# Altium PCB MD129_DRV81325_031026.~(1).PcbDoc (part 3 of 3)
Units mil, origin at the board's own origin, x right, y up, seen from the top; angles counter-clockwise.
Board outline 4300.91 x 4001.52 mil, 4 copper layers (Top Layer, GND, PWR, Bottom Layer), stack 92.668 mil thick; 212 components, 89 nets, 489 pads, 980 vias.

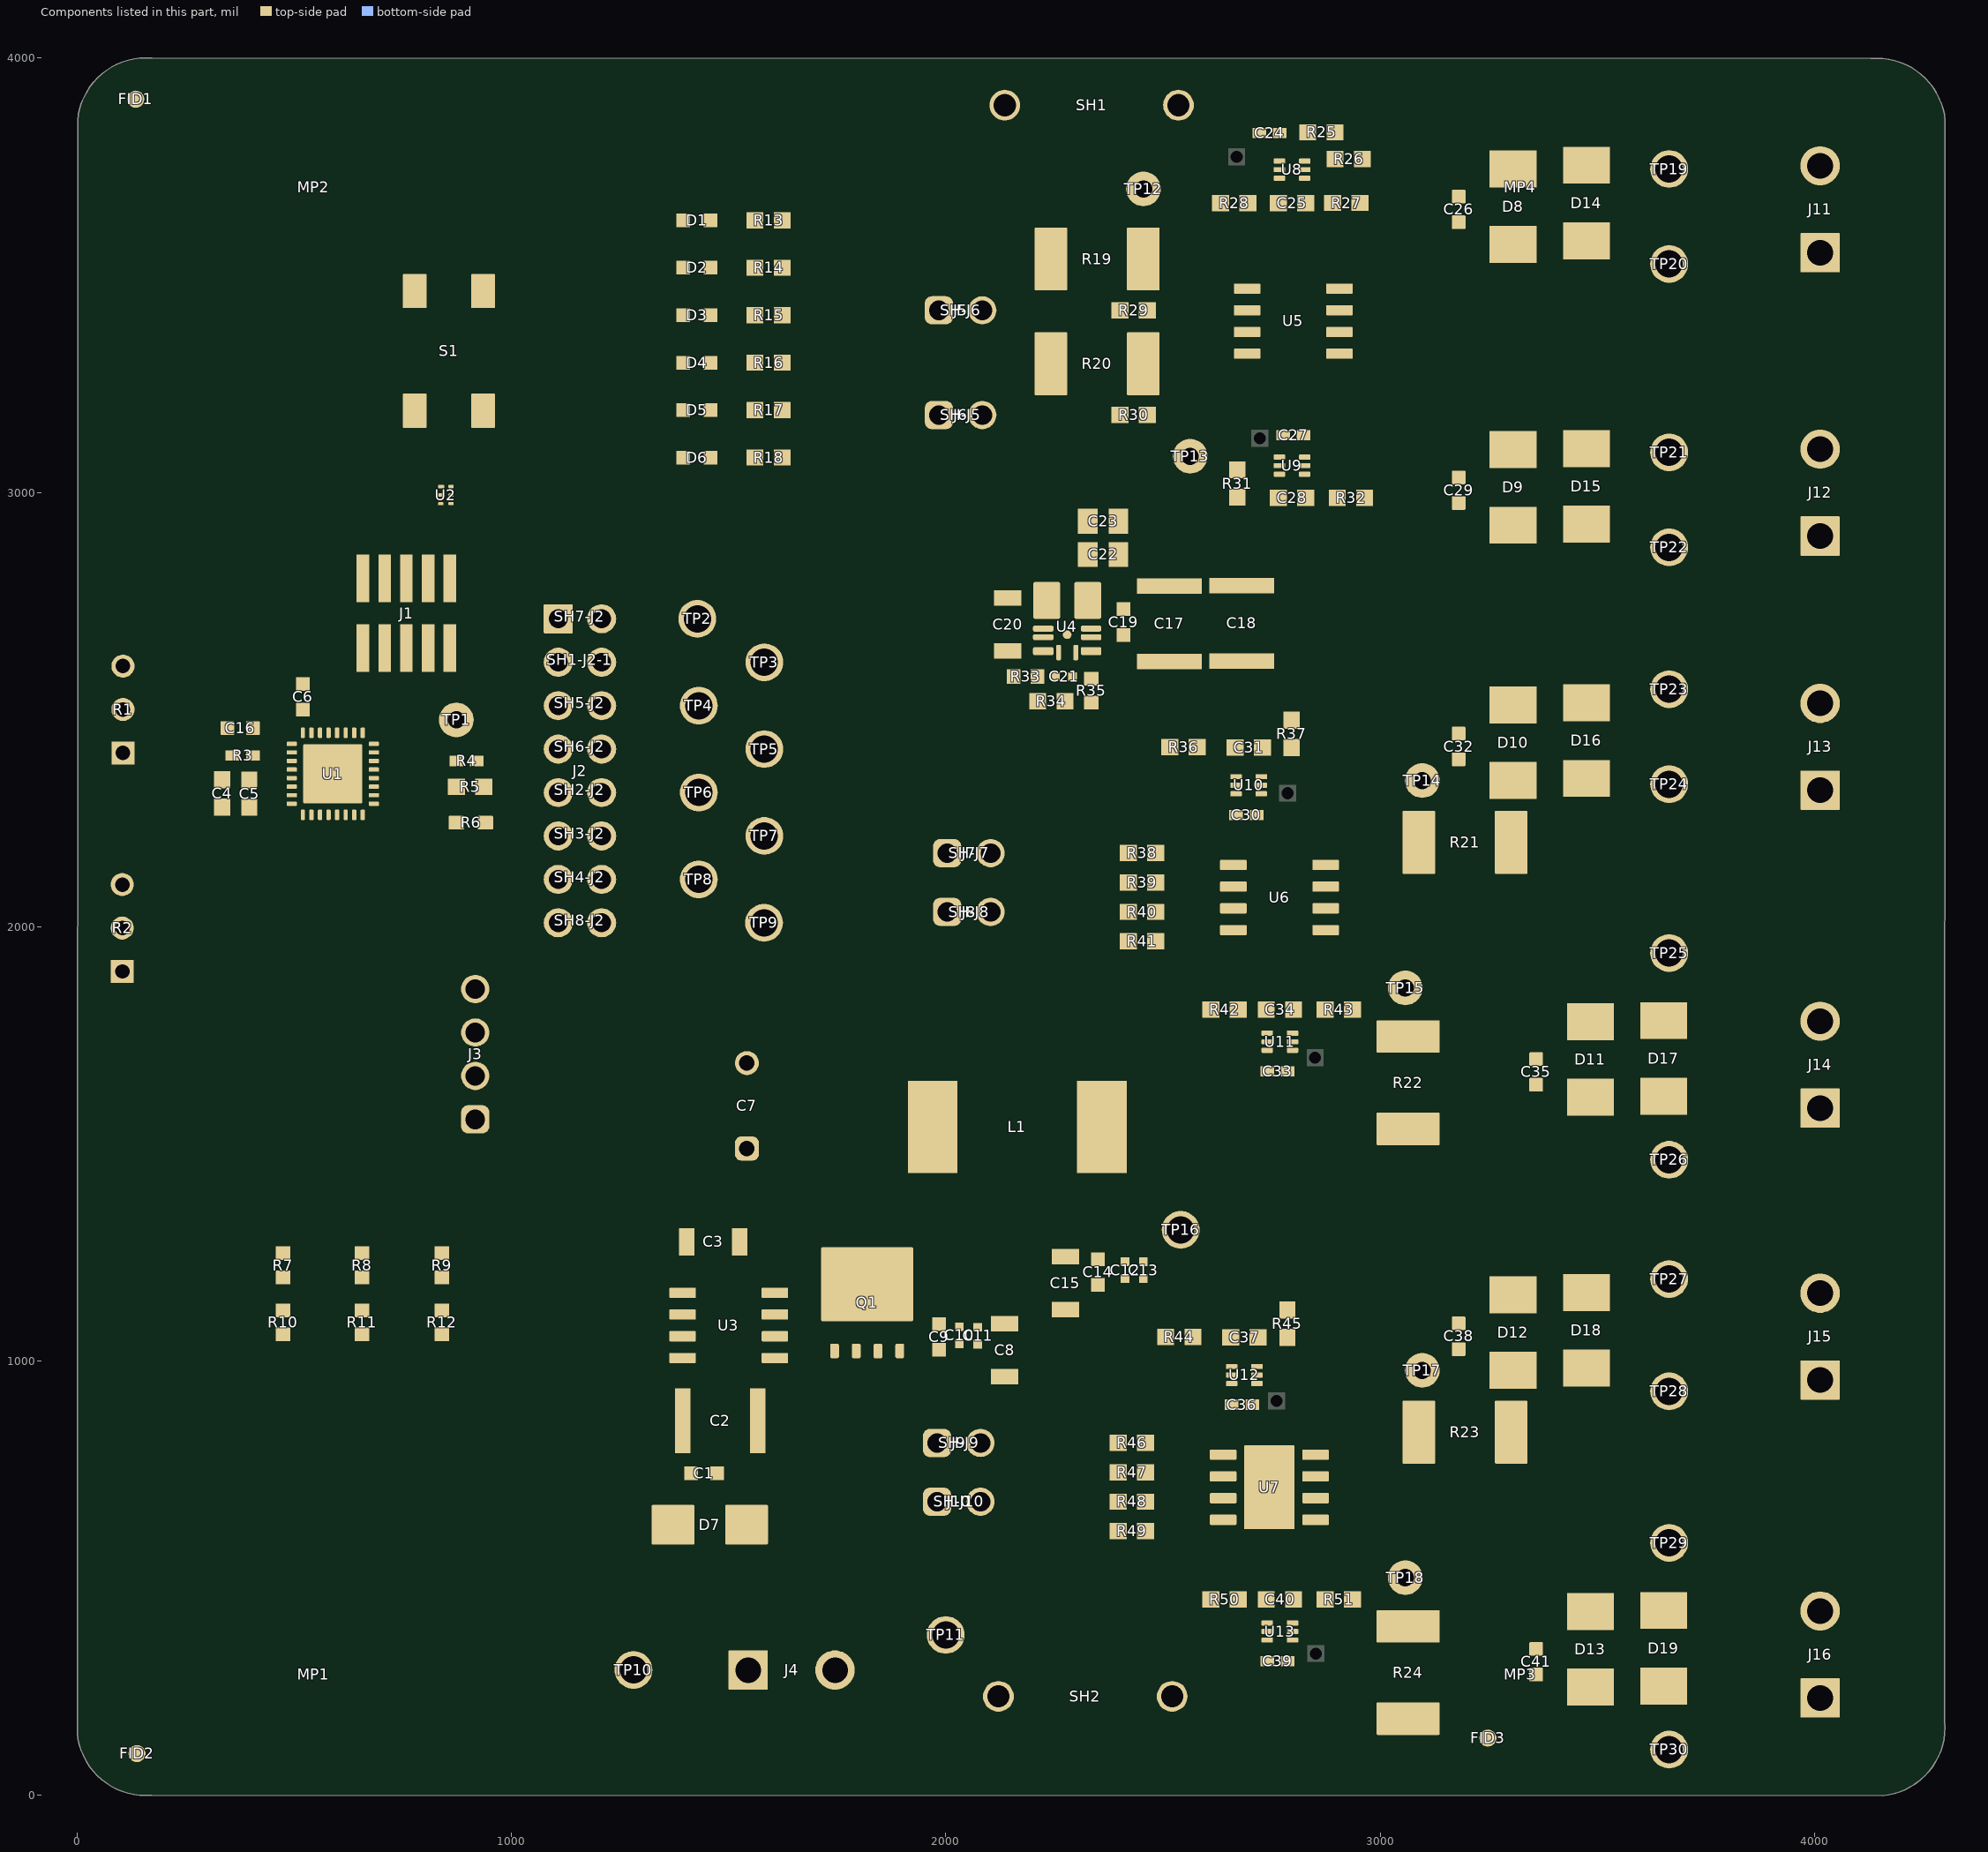
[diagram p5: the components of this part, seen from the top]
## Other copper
Top Layer:
  pour cut-out: 85.34,3905.43 ccw(c134.63,3905.43) 134.63,3856.14 ccw(c134.63,3905.43) 183.93,3905.43 ccw(c134.63,3905.43) 134.63,3954.72 ccw(c134.63,3905.43)
  pour cut-out: 88.06,95.78 ccw(c137.35,95.78) 137.35,46.49 ccw(c137.35,95.78) 186.64,95.78 ccw(c137.35,95.78) 137.35,145.08 ccw(c137.35,95.78)
  pour cut-out: 3198.71,131.5 ccw(c3248.01,131.5) 3248.01,82.21 ccw(c3248.01,131.5) 3297.3,131.5 ccw(c3248.01,131.5) 3248.01,180.79 ccw(c3248.01,131.5)
  region net nRST: 389.18,2407.61 429.46,2407.61 435.57,2401.5 435.57,2386.85 426,2377.29 392.64,2377.29 389.89,2377.29 384.19,2382.99 384.19,2403.54 387.96,2407.3
  region net nRST: 846.71,3006.94 845.09,3005.32 808.41,3005.32 798.93,2995.84 780.72,2995.84 776.23,3000.33 776.23,3017.92 789.32,3031.01 804.17,3031.01 812.65,3022.53 843.21,3022.53 847.7,3018.04 847.7,3008.19 846.71,3007.19
  region net BUCK_3V3: 254.59,2313.38 240.97,2327 240.97,2409.73 246.09,2414.86 365.49,2414.86 375.33,2405.02 375.33,2378.68 386.11,2367.91 453.12,2367.91 505.15,2367.91 506.71,2366.35 506.71,2358.12 503.64,2355.04 476.31,2355.04 450.69,2329.41 450.69,2321.93 442.14,2313.38 424.33,2313.38
  region net GND: 515.97,2347.49 520.42,2351.95 520.42,2418.67 521.61,2419.86 655.05,2419.86 656.25,2418.67 656.25,2285.23 655.05,2284.03 521.61,2284.03 520.42,2285.23 520.42,2332.02 516.36,2336.08 482.7,2336.08 481.36,2337.42 481.36,2346.47 482.38,2347.49
  region net BUCK_3V3: 841.01,2744.89 841.01,2860.4 848.95,2868.34 953.39,2868.34 959.2,2862.53 959.2,2741.87 949.82,2732.49 853.41,2732.49
  region net BUCK_3V3: 875.58,3005.19 888.77,3005.19 891.18,3007.6 891.18,3022.38 885.84,3027.72 858.39,3027.72 854.62,3023.95 854.62,3010.7 860.13,3005.19
  region net SRC2_U1_D: 2506.76,3202.89 2498.33,3211.49 2403.4,3211.49 2393.82,3221.08 2393.82,3368.37 2409.93,3384.48 2738.72,3384.48 2740.88,3382.33 2740.88,3353.29 2738.31,3350.72 2664.03,3350.72 2646.83,3333.52 2646.83,3299 2694.73,3251.1 2694.73,3029.85 2691.29,3026.41 2517.64,3026.41 2506.27,3037.78
  region net OUT2_U3_ADDA: 2900.18,661.95 2917.13,645.01 2917.13,578.88 2922.03,573.98 3084.71,573.98 3165.05,493.64 3165.05,349.84 3195.79,319.1 4205.85,319.1 4238.46,351.71 4238.46,726.12 4214.13,750.45 3128.93,750.45 3083.53,705.05 2823.38,705.05 2820.63,702.29 2820.63,664.13 2822.8,661.95
  region net OUT1_U2_AD: 2853.8,2121.72 2844,2131.52 2844,2160.99 2816.55,2188.44 2816.55,2377.39 2833.3,2394.14 2833.3,2631.05 2900.9,2698.65 4211.55,2698.65 4231.54,2678.67 4231.54,2433.44 4209.54,2411.44 3052.48,2411.44 2910.32,2269.28 2910.32,2128.07 2903.98,2121.72
  region net OUT2_U2_AD: 2923.46,2019.11 2940.18,2002.39 2940.18,1939.05 2947.09,1932.14 3108.09,1932.14 3188.43,1851.8 3188.43,1708 3219.17,1677.27 4229.22,1677.27 4261.84,1709.88 4261.84,2084.28 4237.51,2108.61 3125.99,2108.61 3083.69,2066.31 2846.21,2066.31 2844,2064.11 2844.01,2021.48 2846.37,2019.11
  region net SRC1_U2_AD: 2850.25,2072.82 2844,2079.07 2844,2111.24 2847.24,2114.65 2906.99,2114.65 2918.17,2125.83 2918.17,2266.83 3056.43,2405.1 3137.02,2405.1 3156.78,2385.33 3156.78,2149.17 3080.44,2072.82
  region net SRC2_U2_AD: 2964.08,1695.7 2935.33,1695.7 2916.34,1714.69 2916.34,1827.5 2907.92,1835.92 2858.51,1835.92 2843.15,1851.28 2843.15,2005.9 2846.83,2009.58 2923.23,2009.58 2932.36,2000.45 2932.36,1935.05 2941.74,1925.67 3102.7,1925.67 3180.92,1847.45 3180.92,1704.91 3171.72,1695.7
  region net SRC1_U3_ADDA: 2820.63,744.63 2831.82,755.82 2885.45,755.82 2893.28,763.66 2893.29,906.71 3033.51,1046.93 3137.02,1046.93 3156.78,1027.16 3156.78,791.01 3078.76,712.98 2831,712.98 2820.63,723.36
  region net VM: 3396.33,1032.92 3406.28,1042.87 4208.34,1042.87 4231.54,1019.67 4231.54,793.92 4196.27,758.65 3420.71,758.65 3396.33,783.03
  region net 3V3: 1405.11,3014.62 1330.15,3014.62 1324.48,3020.29 1324.48,3433.5 1334.85,3443.88 1409.36,3443.88 1417.62,3435.62 1417.62,3027.32
  region net 3V3: 1370.49,3608.64 1351.34,3608.64 1346.62,3613.36 1346.62,3637.56 1352.24,3643.54 1409.09,3643.54 1410.43,3642.19 1410.44,3610.69 1408.38,3608.64
  region net 3V3: 2635.93,2239.52 2626.65,2248.8 2626.65,2263.04 2636.67,2273.07 2644.63,2273.07 2654.89,2283.32 2654.89,2310.75 2657.8,2313.67 2678.35,2313.67 2683.83,2308.19 2683.83,2256.6 2683.83,2243.2 2680.14,2239.52
  region net 3V3: 2370.18,1939.09 2360.11,1949.15 2360.11,1987.58 2366.08,1993.55 2430.92,1993.55 2439.48,1984.99 2439.48,1947.58 2430.99,1939.09
  region net 3V3: 2370.18,2074.38 2360.11,2084.45 2360.11,2122.88 2366.08,2128.85 2430.92,2128.85 2439.48,2120.29 2439.48,2082.88 2430.99,2074.38
  region net 3V3: 2346.8,580.92 2336.73,590.99 2336.73,629.41 2342.7,635.39 2407.54,635.39 2416.11,626.82 2416.11,589.42 2407.61,580.92
  region net 3V3: 2346.8,716.22 2336.73,726.29 2336.73,764.71 2342.7,770.69 2407.54,770.69 2416.11,762.12 2416.11,724.72 2407.61,716.22
  region net OUT1_U3_ADDA: 2830.43,763.56 2820.63,773.36 2820.63,802.82 2789.82,833.63 2789.82,1002.37 2820.63,1033.18 2820.63,1283.6 2877.52,1340.49 4188.18,1340.49 4208.16,1320.5 4208.16,1075.27 4186.16,1053.28 3029.1,1053.28 2886.95,911.12 2886.95,769.9 2880.6,763.56
  region net SRC2_U3_ADDA: 2899.85,651.42 2908.99,642.28 2908.99,576.89 2918.36,567.51 3079.32,567.51 3157.55,489.29 3157.54,346.74 3148.34,337.54 2918.45,337.54 2908.99,347 2908.99,466.46 2897.69,477.76 2835.13,477.76 2819.77,493.12 2819.77,647.74 2823.45,651.42
  region net VM: 4208.54,1407.53 3607.63,1407.53 3574.21,1440.95 3574.21,1644.97 3593.42,1666.65 4212.46,1666.65 4231.54,1647.57 4231.54,1430.52
  region net SRC1_U3_ADDA: 2810.06,1088.59 2814.46,1092.99 2814.46,1196.19 2807.47,1203.18 2762.07,1203.18 2756.91,1198.02 2756.91,1094.49 2762.81,1088.59
  region net 3V3: 2673.83,952.49 2671.81,954.5 2622.76,954.5 2616.89,948.64 2616.89,877.97 2622.29,872.58 2659.06,872.58 2673.83,887.34
  region net VM: 2630.54,1723.41 2605,1748.94 2250.99,1748.94 2223.28,1721.63 2223.28,1221.14 2227.56,1216.86 2580.46,1216.86 2630.54,1266.95
  region net PI_IN: 2174.22,1067.25 2178.74,1071.77 2178.74,1750.03 2157.69,1771.08 1725.14,1771.08 1479.69,1525.63 1479.69,1164.66 1511.24,1133.11 1645.6,1133.11 1711.46,1067.25
  region net 3V3: 852.08,1223.04 442.43,1223.04 430.41,1235.05 430.41,1317.52 434.49,1321.6 851.38,1321.6 868.48,1304.49 868.48,1236.65 852.08,1220.24
  region net VM: 4177.27,40.38 3616.61,40.38 3574.21,82.79 3574.21,286.8 3593.42,308.48 4209.9,308.48 4231.54,286.84 4231.54,94.65
  region net BUCK_3V3: 2352.65,2816.65 2252.21,2816.65 2243.04,2825.82 2243.04,2953.07 2257.96,2967.99 2355.24,2967.99 2366.14,2957.09 2366.14,2829.75
  region net 3V3: 2755.74,361.82 2753.72,363.83 2704.67,363.83 2698.8,357.97 2698.8,287.3 2704.2,281.9 2740.97,281.9 2755.74,296.67
  region net 3V3: 2755.74,1719.98 2753.72,1722 2704.67,1722 2698.8,1716.13 2698.8,1645.46 2704.2,1640.07 2740.97,1640.07 2755.74,1654.84
  region net SRC1_U2_AD: 2820.06,2446.76 2825.32,2452.01 2825.32,2553.49 2817.47,2561.35 2772.07,2561.35 2766.91,2556.19 2766.91,2452.65 2772.81,2446.76
  region net 3V3: 2766.58,3901.36 2752.99,3887.77 2752.99,3808.54 2804.6,3756.92 2805.59,3756.92 2840.99,3756.92 2852.8,3768.73 2852.8,3887.92 2844.49,3896.23 2839.9,3901.36
  region net 3V3: 2881.56,3100.01 2881.56,3144.3 2861.08,3164.78 2809.12,3164.78 2803.89,3159.55 2803.89,3085.68 2814.3,3075.27 2856.82,3075.27
  region net OUT2_U1_D: 2865.92,3237.52 2984.58,3237.52 2997.22,3224.88 2997.22,3035.19 3014.68,3017.73 3227.59,3017.73 4174.57,3017.73 4231.54,3074.69 4231.54,3302.86 4184.81,3349.59 3398.58,3349.59 3357.91,3390.26 2878.35,3390.26 2859.05,3370.73 2859.05,3244.39
  region net OUT1_U1_D: 2858.99,3548.02 2866.12,3555.15 2973.58,3555.15 3008.73,3590.3 3008.73,3898.43 3040.19,3929.89 4149.81,3929.88 4231.54,3848.16 4231.54,3661.84 4226.17,3656.47 3153.25,3656.47 3137.07,3640.29 3137.07,3426.38 3113.26,3402.57 2866,3402.57 2858.99,3409.59
  region net SRC1_U1_D: 2740.88,3591.64 2729.61,3602.91 2669.57,3602.91 2658.92,3614.06 2658.92,3706.91 2590.76,3775.06 2413.31,3775.06 2361.4,3723.15 2361.4,3489.74 2396.07,3455.07 2736.51,3455.07 2740.88,3459.44
  region net VM: 3396.33,2963.75 3423.05,2990.47 4209.13,2990.47 4231.54,2968.07 4231.54,2743.54 4198.1,2710.1 3410.74,2710.1 3396.33,2724.51
  region net VM: 3396.33,3616.33 3423.05,3643.05 4225.67,3643.05 4231.54,3637.18 4231.54,3375.61 4218.61,3362.68 3410.74,3362.68 3396.33,3377.09
  region net VM: 3396.33,2391.08 3406.28,2401.03 4208.34,2401.03 4231.54,2377.83 4231.54,2152.08 4196.27,2116.81 3420.71,2116.81 3396.33,2141.19
  region net BUCK_3V3: 2276.25,2589.53 2275.57,2588.84 2275.57,2558.45 2254.58,2537.47 2254.58,2488.28 2272.28,2470.58 2342.45,2470.58 2353.82,2481.94 2353.82,2533.46 2352.19,2535.09 2322.29,2535.09 2306.12,2551.26 2306.12,2586.79 2303.39,2589.52
  region net VM: 2755.13,2487.79 2755.13,2568.51 2765.23,2578.61 2765.23,2674.96 2741.69,2698.5 2312.24,2698.5 2306.51,2692.77 2306.51,2663.92 2316.09,2654.34 2359.98,2654.34 2365.83,2648.49 2365.83,2517.01 2418.4,2464.44 2731.77,2464.44
  region net GND: 2273.76,2613.41 2271.46,2615.72 2271.46,2629.34 2273.76,2631.65 2273.76,2649.89 2268.31,2655.34 2268.31,2671.17 2269.41,2672.27 2289.25,2672.27 2304.8,2656.73 2304.8,2614.61 2303.61,2613.41
  region net VM_IN: 1193.94,551.46 1416.87,551.46 1449.97,584.56 1449.8,672.56 1449.8,1055.71 1423.72,1081.79 1365.06,1081.79 1356.56,1090.29 1356.56,1120.96 1360.99,1125.39 1480.51,1125.39 1577.48,1028.43 1703.65,1028.43 1715.1,1039.88 1851.48,1039.88 1861.06,1030.29 1861.06,513.96 1621.8,274.7 1621.8,48.1 1600.99,27.29 1159.35,27.29 1137.38,49.25 1137.38,494.9
  text ".Layer_Name" at -287.12,-1133.2 h60
GND:
  text ".Layer_Name" at -287.12,-1133.2 h60
PWR:
  text ".Layer_Name" at -287.12,-1133.2 h60
Bottom Layer:
  region net SRC1_U3_ADDA: 2827.76,1145.54 2832.97,1150.75 2832.97,1200.55 2828.75,1204.76 2763.65,1204.76 2754.01,1195.12 2754.01,1150.67 2759.14,1145.54
  region net SRC1_U2_AD: 2837.76,2503.71 2842.97,2508.91 2842.97,2558.71 2838.75,2562.93 2773.65,2562.93 2764.01,2553.28 2764.01,2508.84 2769.14,2503.71
  region net BUCK_3V3: 2324.65,2947.16 2343.51,2928.31 2343.51,2884.69 2328.99,2870.17 2187.63,2870.17 2167.66,2890.14 2167.66,2929.2 2185.62,2947.16
  text ".Layer_Name" at -287.12,-1133.2 h60

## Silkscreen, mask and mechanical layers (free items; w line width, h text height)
Top Overlay:
  drawing of 190 lines, arcs and shapes, not listed
  text "CSA 1" at 2621.76,3902.66 h60
  text "DRV81325-Q1" at 1283.61,3873.82 h110
  text "MSPM0" at 626.47,3872.73 h118.11
  text "RECIRC" at 3351.79,3871.86 h30
  text "OUT1_U1" at 3838.75,3863.65 h80
  text "TVS" at 3250.08,3825.08 h30
  text "OUT1_U1" at 3540.34,3822.31 h70
  text "GND" at 2167.47,3779.7 h106.3
  text "LED STATUS" at 1316.81,3721.5 h70
  text "3V3_STATUS" at 1462.62,3654.96 h30
  text "SRC1_U1" at 2150.17,3623.21 h59.06
  text "DRV81325-Q1 EVM" at 96.27,3580.46 h95
  text "MCU_STATUS" at 1462.62,3548.43 h30
  text "MD129E1" at 204.98,3470.42 h108.27
  text "STATUS1_U6" at 1455.29,3437.97 h30
  text "VM" at 3629.39,3390.46 h70
  text "STATUS2_U6" at 1462.62,3327.74 h30
  text "RECIRC" at 3351.79,3225.3 h30
  text "STATUS1_U7" at 1462.62,3217.82 h30
  text "DRV81325D" at 2627.31,3216.24 h40
  text "OUT2_U1" at 3838.75,3211.08 h80
  text "TVS" at 3250.08,3178.52 h30
  text "OUT2_U1" at 3540.34,3169.73 h70
  text "STATUS2_U7" at 1462.62,3106.64 h30
  text "ESD PROTECTION" at 668.74,3043.15 h45
  text "SRC2_U1" at 2260.98,3006.95 h59.06
  text "10-PIN ARM CONNECTOR" at 581.35,2904.1 h45
  text "CSA 2" at 2638.32,2853.25 h60
  text "VM" at 3629.98,2740.42 h70
  text "PWM_IN1" at 24.54,2736.4 h80
  text "0%" at 138.84,2673.85 h35
  text "3V3" at 1666.57,2668.97 h80
  text "RECIRC" at 3351.79,2637.44 h30
  text "OUT1_U2" at 3807.77,2626.52 h80
  text "OUT1_U2" at 3540.38,2624.31 h70
  text "TVS" at 3250.08,2590.66 h30
  text "IN1" at 1658.61,2565.91 h75
  text "CSA 3" at 2499.29,2518.91 h60
  text "IN2" at 1658.61,2465.91 h75
  text "BUCK 3V3 SUPPLY" at 2047.78,2421.12 h65 r90
  text "STATUS1_U6" at 1658.23,2380.19 h55
  text "100%" at 92.25,2283.99 h35
  text "STATUS2_U6" at 1666.18,2283.36 h55
  text "BSL INVOKE" at 1041.65,2273.91 h55 r90
  text "VM" at 3631.23,2194.82 h70
  text "STATUS1_U7" at 1675.9,2181.75 h55
  text "0%" at 134.43,2171.99 h35
  text "VM MONITORING" at 669.84,2131.36 h55
  text "STATUS2_U7" at 1667.93,2081.01 h55
  text "SRC1_U2" at 3038.07,2020.51 h59.06
  text "OUT2_U2" at 3540.38,2016.8 h70
  text "GND" at 1677.16,1972.28 h80
  text "RECIRC" at 3407.94,1918.47 h30
  text "OUT2_U2" at 3838.75,1893.83 h80
  text "DRV81325AQD" at 2554.91,1883.79 h40
  text "TVS" at 3405.28,1863.73 h30
  text "PA1" at 727.81,1826.5 h59.06
  text "SRC2_U2" at 3117.77,1793.68 h59.06
  text "100%" at 113.04,1779.89 h35
  text "PA5" at 728.19,1726.5 h59.06
  text "PWM_IN2" at 16.51,1672.12 h80
  text "PA10" at 698.87,1623.91 h59.06
  text "CSA 4" at 2597.47,1569.52 h60
  text "PA0" at 726.56,1527 h59.06
  text "AUXILARY MCU PINS" at 644.93,1434.57 h55
  text "VM" at 3587.44,1420.46 h70 r90
  text "DEVICE ID" at 321.65,1305.73 h60
  text "RECIRC" at 3351.79,1279.28 h30
  text "OUT1_U3" at 3838.75,1267.49 h80
  text "OUT1_U3" at 3540.38,1266.15 h70
  text "TVS" at 3250.08,1232.5 h30
  text "CSA 5" at 2499.29,1160.29 h60
  text "DEV_ID2" at 589.66,1048.18 h59.06 r90
  text "DEV_ID1" at 403.44,1045.83 h59.06 r90
  text "DEV_ID3" at 771.44,1046.67 h59.06 r90
  text "VM" at 3626.47,797.94 h70
  text "SRC1_U3" at 3070.67,660.11 h59.06
  text "OUT2_U3" at 3540.38,658.64 h70
  text "RECIRC" at 3407.94,560.31 h30
  text "OUT2_U3" at 3799.42,538.17 h80
  text "DRV81325ADDA" at 2509.52,532.18 h40
  text "TVS" at 3405.29,505.56 h30
  text "SRC2_U3" at 3114.95,433.76 h59.06
  text "GND" at 2233.69,262.14 h106.3
  text "CSA 6" at 2597.47,220.33 h60
  text "6V TO 18V" at 775.84,195.25 h90
  text "VM" at 3587.44,62.3 h70 r90
  text "VM" at 1207.65,48.3 h137.8
  text "GND" at 1867.24,46.43 h137.8
  text ".Layer_Name" at 40.84,-1133.2 h60
Bottom Overlay:
  lines w10: 144.14,1896.85 197.88,1897.63 ; 144.14,1996.85 197.88,1997.63 ; 144.14,2096.85 197.88,2097.63 ; 145.65,2400.02 199.4,2400.8 ; 145.65,2500.02 199.4,2500.8 ; 145.65,2600.02 199.4,2600.8 ; 1248.7,2008.57 1528.43,2008.48 ; 1248.7,2208.57 1528.43,2208.48 ; 1248.7,2408.57 1528.43,2408.48 ; 1248.7,2608.57 1528.43,2608.48 ; 1249.64,2108.15 1372.69,2109.27 ; 1249.64,2308.15 1372.69,2309.27 ; 1249.64,2508.15 1372.69,2509.27 ; 1249.64,2708.15 1372.69,2709.27 ; 1885.23,674.99 1938.97,675.77 ; 1885.23,810.29 1938.97,811.07 ; 1889.64,3177.3 1943.39,3178.08 ; 1889.64,3418.53 1943.39,3419.31 ; 2002.14,2263.55 2002.92,2209.8 ; 2002.92,1993.37 2003.7,1939.62
  text "OUT1_U1" at 4157.5,3806.72 h80
  text "OUT1_U1" at 3828.62,3801.99 h80
  text "SRC1_U1" at 2598.5,3543.48 h80
  text "VM" at 4064.81,3426.58 h80
  text "VM" at 3717.15,3400.58 h80
  text "IN1" at 1875.86,3390.53 h80
  text "OUT2_U1" at 4157.5,3154.15 h80
  text "IN2" at 1875.86,3149.3 h80
  text "OUT2_U1" at 3809.83,3146.82 h80
  text "SRC2_U1" at 2706.09,2927.92 h80
  text "VM" at 4064.81,2774.01 h80
  text "VM" at 3717.15,2748 h80
  text "3V3" at 1749.84,2674.61 h80
  text "OUT1_U2" at 3809.83,2601.4 h80
  text "OUT1_U2" at 4157.5,2568.72 h80
  text "IN1" at 1922.59,2566.53 h75
  text "GND" at 451.4,2563.71 h80
  text "IN2" at 1768.25,2466.93 h75
  text "POT_IN1" at 487.42,2458.42 h80
  text "STATUS1_U6" at 1920.35,2367.58 h55
  text "BUCK_3V3" at 525.09,2358.42 h80
  text "IN1" at 2064.58,2275.03 h80
  text "STATUS2_U6" at 1760.13,2269.81 h55
  text "VM" at 3717.15,2202.58 h80
  text "VM" at 4064.81,2188.59 h80
  text "SRC1_U2" at 3240.42,2181.07 h80
  text "STATUS1_U7" at 1912.03,2168.23 h55
  text "STATUS2_U7" at 1760.79,2069.49 h55
  text "GND" at 449.88,2060.54 h80
  text "OUT2_U2" at 3809.83,1993.89 h80
  text "GND" at 1871.49,1974.75 h80
  text "POT_IN2" at 485.9,1955.25 h80
  text "BUCK_3V3" at 523.57,1855.25 h80
  text "IN2" at 2073.19,1853.45 h80
  text "OUT2_U2" at 4157.5,1836.9 h80
  text "SRC2_U2" at 3201.28,1703.73 h80
  text "VM" at 3726.52,1523.46 h80
  text "VM" at 4064.81,1456.76 h80
  text "OUT1_U3" at 4157.5,1210.56 h80
  text "OUT1_U3" at 3801.75,1048.61 h80
  text "SRC1_U3" at 3240.8,1040.51 h80
  text "VM" at 4064.81,830.42 h80
  text "VM" at 3728.14,799.24 h80
  text "IN1" at 1870.35,776.39 h80
  text "IN2" at 1874.93,645.74 h80
  text "OUT2_U3" at 3798.35,634.15 h80
  text "SRC2_U3" at 3201.66,563.17 h80
  text "OUT2_U3" at 4157.5,478.73 h80
  text "VM" at 3725.23,165.25 h80
  text "VM" at 4064.81,98.6 h80
  text "VM" at 1400.35,48.3 h137.8
  text "GND" at 2108.83,48.3 h137.8
  text ".Layer_Name" at -287.12,-1133.2 h60
Top Paste:
  text ".Layer_Name" at -287.12,-1133.2 h60
Bottom Paste:
  text ".Layer_Name" at -287.12,-1133.2 h60
Top Solder:
  text ".Layer_Name" at -287.12,-1133.2 h60
  text ".Layer_Name" at -287.12,-1133.2 h60
Bottom Solder:
  text ".Layer_Name" at -287.12,-1133.2 h60
Drill Guide:
  text ".Layer_Name" at -287.12,-1133.2 h60
M1 Board Outline:
  lines w10: -0.03,143.05 ccw(c156.84,156.9) 170.69,0.03 ; 0.03,142.38 0.82,3856.95 cw(c157.69,3843.1) 171.55,3999.97 4130.95,3999.12 ; 169.89,-0.04 4157.62,-0.88 ; 4130.16,3999.05 cw(c4144.01,3842.18) 4300.88,3856.04 ; 4156.95,-0.94 ccw(c4143.1,155.92) 4299.97,169.78 ; 4300.04,168.98 4300.82,3856.71
  text ".Layer_Name" at -287.12,-1133.2 h60
M2 Board Dimensions:
  rectangle: -864.12,-549.71 -739.12,-424.71
  rectangle: -739.12,-674.71 -364.12,-549.71
  lines w7: -864.12,-549.71 135.88,-549.71 ; -739.12,-674.71 -739.12,-424.71 ; -614.12,-674.71 -614.12,-424.71 ; -364.12,-674.71 -364.12,-424.71 ; -114.12,-674.71 -114.12,-424.71 ; -864.12,-674.71 135.88,-674.71 135.88,-424.71 -864.12,-424.71 -864.12,-674.71
  text ".Layer_Name" at -287.12,-1133.2 h60
M3 3D STEP Top:
  text ".Layer_Name" at -287.12,-1133.2 h60
M4 3D STEP Bottom:
  text ".Layer_Name" at -287.12,-1133.2 h60
M5 Assembly Top:
  lines w10: -1156.12,-1204.87 5443.88,-1204.87 ; -1156.12,-1001.54 5445.88,-1001.54 ; -1156.12,-798.21 -1156.12,-1408.21 2848.88,-1408.21 5445.88,-1408.21 5445.88,-798.21 -1155.62,-798.21 -1155.62,-1408.21 419.88,-1408.21 ; 1308.88,-1408.21 1308.88,-798.21 ; 2575.88,-1001.54 2575.88,-798.21 ; 3415.88,-1001.54 3415.88,-798.21 ; 4037.88,-1414.71 4037.88,-1211.87
  text "COMPONENTS MARKED 'DNP' SHOULD NOT BE POPULATED." at 289.38,-593.21 h60
  text "ASSEMBLY VARIANT:" at 288.88,-708.71 h60
  text ".VariantName" at 1324.88,-708.71 h60
  text "PCB VIEWED FROM TOP SIDE" at -1092.62,-930.37 h60
  text "BOARD #:" at 1383.88,-930.37 h60
  text ".PRJ_Number" at 1929.38,-930.37 h60
  text "REV:" at 2773.88,-930.37 h60
  text ".PCB_Rev" at 3065.38,-930.37 h60
  text "SVN REV:" at 3611.88,-930.37 h60
  text ".VersionControl_RevNumber" at 4117.88,-930.37 h60
  text "TID #:" at 1383.88,-1133.71 h60
  text ".TID" at 1929.38,-1133.71 h60
  text "PLOT NAME =" at -1092.62,-1339.04 h60
  text ".plot_File_Name" at -287.12,-1339.04 h60
  text "GENERATED    :" at 1385.88,-1339.04 h60
  text ".Print_Date" at 2255.38,-1339.04 h60
  text ".Print_Time" at 2984.38,-1339.04 h60
  text "TEXAS INSTRUMENTS" at 4248.88,-1339.04 h60
M6 Assembly Bottom:
  lines w10: -1156.62,-1002.04 5445.38,-1002.04 ; -1154.62,-1205.37 5445.38,-1205.37 ; 251.38,-1415.21 251.38,-1212.37 ; 873.38,-1002.04 873.38,-798.71 ; 1713.38,-1002.04 1713.38,-798.71 ; 2980.38,-1408.71 2980.38,-798.71 ; 3869.38,-1408.71 5444.88,-1408.71 5444.88,-798.71 -1156.62,-798.71 -1156.62,-1408.71 1440.38,-1408.71 5445.38,-1408.71 5445.38,-798.71
  text "COMPONENTS MARKED 'DNP' SHOULD NOT BE POPULATED." at 5237.88,-592.71 h60
  text ".VersionControl_RevNumber" at 9716.26,-647.71 h60
  text ".VariantName" at 4193.88,-708.71 h60
  text "ASSEMBLY VARIANT:" at 5232.88,-708.71 h60
  text "SVN REV:" at 677.38,-930.87 h60
  text ".PCB_Rev" at 1223.88,-930.87 h60
  text "REV:" at 1515.38,-930.87 h60
  text ".PRJ_Number" at 2359.88,-930.87 h60
  text "BOARD #:" at 2905.38,-930.87 h60
  text "PCB VIEWED FROM BOTTOM SIDE" at 5381.88,-930.87 h60
  text ".TID" at 2359.88,-1134.21 h60
  text "TID #:" at 2905.38,-1134.21 h60
  text "TEXAS INSTRUMENTS" at 40.38,-1339.54 h60
  text ".Print_Time" at 1304.88,-1339.54 h60
  text ".Print_Date" at 2033.88,-1339.54 h60
  text "GENERATED    :" at 2903.38,-1339.54 h60
  text ".plot_File_Name" at 4576.38,-1339.54 h60
  text "PLOT NAME =" at 5381.88,-1339.54 h60
M9 Title Sheet:
  drawing of 57 lines, arcs and shapes, not listed
  text "1" at -124.29,8761.79 h70
  text "2" at 2371.38,8761.79 h70
  text "3" at 4860.72,8761.79 h70
  text "4" at 7367.39,8761.79 h70
  text "5" at 9866.38,8761.79 h70
  text "6" at 12371.38,8761.79 h70
  text "A" at -1280.62,6618.79 h70
  text "A" at 13519.38,6618.79 h70
  text "B" at -1280.62,4238.79 h70
  text "B" at 13519.38,4238.79 h70
  text "C" at -1280.62,1863.79 h70
  text "C" at 13519.38,1863.79 h70
  text "PROJECT TITLE:" at 10479.38,2.79 h45
  text "MD129_DRV81325" at 10529.38,-130.53 h70
  text "DESIGNED FOR:" at 10479.38,-298.21 h45
  text ".PRJ_Customer" at 10529.38,-438.21 h70
  text "D" at -1280.62,-506.21 h70
  text "D" at 13519.38,-506.21 h70
  text "FILE NAME:" at 10479.38,-598.21 h45
  text ".PCB_File_Name_No_Path" at 10529.38,-718.21 h70
  text "Texas Instruments (TI) and/or its licensors do not warrant the accuracy or completeness of this specification" at 5509.88,-880.04 h45
  text "ENGINEER:" at 10479.38,-888.21 h45
  text "LAYOUT BY:" at 11984.38,-888.21 h45
  text "or any information contained therein. TI and/or its licensors do not warrant that this design will meet" at 5464.89,-992.71 h45
  text ".PRJ_Engineer" at 10529.38,-1043.2 h70
  text "PACTRON" at 12034.88,-1043.2 h70
  text "the specifications, will be suitable for your application or fit for any particular purpose, or will operate in" at 5464.89,-1105.37 h45
  text ".Layer_Name" at -287.12,-1133.2 h60
  text "ALTIUM DESIGNER VERSION:" at 11984.38,-1198.21 h45
  text "an implementation. TI and/or its licensors do not warrant that the design is production worthy. You should" at 5464.89,-1218.04 h45
  text "completely validate and test your design implementation to confirm the system functionality for your application." at 5509.88,-1330.71 h45
  text ".print_Scale" at 10529.38,-1331.53 h70
  text ".Application_BuildNumber" at 12034.88,-1331.53 h70
  text "1" at -124.29,-1538.21 h70
  text "2" at 2371.38,-1538.21 h70
  text "3" at 4860.72,-1538.21 h70
  text "4" at 7367.39,-1538.21 h70
  text "5" at 9866.38,-1538.21 h70
  text "6" at 12371.38,-1538.21 h70
M10 Fab Notes:
  drawing of 189 lines, arcs and shapes, not listed
  text "FAB NOTE:" at -720.63,8127.29 h120
  text "1.NO VENDOR LOGO OR NAME ON THE BOARD" at -518.36,7928.55 h100
  text "2.ALL HOLES SHOULD BE FHS." at -518.36,7757.05 h100
  text "3.CLIP SILKSCREEN ON NO MASK AREA." at -518.36,7585.55 h100
  text "4.NEED TO REMOVE THE NON FUNCTIONAL PADS IN INNER LAYERS." at -518.36,7414.05 h100
  text "5.VIA PLUGGING: YES, ALL 7.87 , 8 MIL DRILLS ARE NEED TO BE SOLDER MASK OR NON-CONDUCTIVE VIA PLUGGING FROM COMPONENT BOTTOM SIDE." at -518.36,7209.22 h100
  text "6.TAIYO INK - GREEN MATTE NEED TO BE FOLLOWED" at -518.36,7037.72 h100
  text "DESIGN INFORMATION" at 11517.89,6081.47 h60
  text "MIN. TRACK WIDTH:" at 10873.33,5949.34 h60
  text "10" at 11969.58,5949.35 h60
  text "MIL" at 12124.33,5949.34 h60
  text "MIN. CLEARANCE:" at 10873.33,5825.22 h60
  text "MIL" at 12124.33,5825.22 h60
  text "6" at 11971.82,5820.67 h60
  text "14" at 11950.79,5702.13 h60
  text "MIN. VIA PAD SIZE:" at 10873.33,5701.09 h60
  text "MIL" at 12124.33,5701.09 h60
  text "0.05mm (2MIL)" at 11568.33,5571.19 h60
  text "MINIMUM ANNULAR RING" at 10544.1,5562.97 h60
  text "EXTERNAL" at 12276.33,5562.97 h60
  text "PER" at 10744.1,5452.84 h60
  text "IPC-D-275 CLASS 2 LEVEL C" at 10964.1,5452.84 h60
  text "MIL, HOLES" at 12452.33,5352.36 h60
  text "+/-" at 12059.88,5343.78 h60
  text "+/-" at 12913.88,5343.78 h60
  text "REGISTRATION TOLERANCES:" at 10544.1,5342.71 h60
  text "METAL" at 11743.88,5342.71 h60
  text "5" at 12320.08,5342.72 h60
  text "3" at 13153.08,5342.72 h60
  text "MIL" at 13269.33,5342.71 h60
  text "HOLE SIZE TOLERANCE (UNLESS OTHERWISE SPECIFIED):" at 10544.1,5244.4 h60
  text "+/-" at 12913.88,5241.53 h60
  text "3" at 13153.08,5240.46 h60
  text "MIL" at 13269.33,5240.46 h60
  text "MATERIAL:" at 10469.33,5102.81 h60
  text "FR-4 High Tg" at 11455.78,4974.29 h60
  text "X" at 11311.34,4966.3 h60
  text "FR-4" at 10890.34,4961.78 h60
  text "OTHER" at 12378.33,4961.78 h60
  text "62 MIL (1.6mm) +/-10%" at 11210.44,4818.75 h60
  text "X" at 12377.34,4818.19 h60
  text "93.47 MIL" at 12810.29,4816.1 h60
  text "THICKNESS:" at 10544.1,4810.53 h60
  text "OTHER" at 12495.34,4810.53 h60
  text "TOLERANCE:" at 10544.1,4672.22 h60
  text "X" at 11392.34,4672.22 h60
  text "ANSI IPC-6012 TYPE 3 CLASS 2" at 11570.35,4672.22 h60
  text "OTHER +/-" at 11570.33,4528.03 h60
  text "BOW & TWIST:" at 10544.1,4382.84 h60
  text "X" at 11392.34,4382.84 h60
  text "ANSI IPC-6012 TYPE 3 CLASS 2" at 11570.35,4382.84 h60
  text "OTHER +/-" at 11570.33,4236.14 h60
  text "DRILLING:" at 10469.33,4105.52 h60
  text "NC_DRILL FILES" at 12230.33,4000.34 h60
  text "REFERENCE:" at 10544.1,3996.4 h60
  text "X" at 11201.34,3996.3 h60
  text "AS SHOWN" at 11379.33,3996.4 h60
  text "X" at 12102.34,3996.4 h60
  text "OTHER" at 12528.33,3854.15 h60
  text "PTH COPPER THICKNESS:" at 10543.78,3850.62 h60
  text "X" at 11683.02,3850.62 h60
  text "20-30 um" at 11811.01,3850.62 h60
  text "BOARD FINISH:" at 10469.33,3703.02 h60
  text "SILKSCREEN:" at 10624.56,3592.89 h60
  text "X" at 11582.34,3592.89 h60
  text "TOP" at 11699.33,3592.89 h60
  text "X" at 12092.34,3592.89 h60
  text "BOTTOM" at 12210.33,3592.89 h60
  text "SILKSCREEN COLOR:" at 10624.56,3437.7 h60
  text "X" at 11581.34,3437.7 h60
  text "WHITE" at 11699.33,3437.7 h60
  text "OTHER" at 12210.33,3437.7 h60
  text "X" at 11712.34,3294.26 h60
  text "GREEN" at 11830.33,3294.26 h60
  text "OTHER" at 12448.33,3294.26 h60
  text "SOLDER RESIST COLOR:" at 10624.56,3287.39 h60
  text "X" at 11712.34,3140 h60
  text "MATTE" at 11830.33,3140 h60
  text "SEMI-GLOSS" at 12447.87,3139.37 h60
  text "IMMERSION GOLD (ENIG)" at 11530.33,2967.23 h60
  text "ENEPIG" at 12867.88,2960.01 h60
  text "SURFACE FINISH:" at 10469.33,2959.01 h60
  text "X" at 11352.34,2959.01 h60
  text "IMM. TIN/SILVER OR EQUIV" at 10798.88,2821.7 h60
  text "OTHER" at 12230.33,2817.76 h60
  text "ARRAY/PANEL:" at 10469.33,2662.38 h60
  text "X" at 11352.34,2658.19 h60
  text "CUT AND TRIM PER M1 BOARD OUTLINE" at 11530.34,2654.16 h60
  text "N.C. ROUTE" at 11530.33,2518.19 h60
  text "V. SCORE" at 12396.33,2518.19 h60
  text "CERTIFICATION:" at 10469.33,2389.07 h60
  text "MATERIALS AND WORKMANSHIP FOR ALL PCBS" at 11194.33,2389.07 h60
  text "TO MEET OR EXCEED THE REQUIREMENTS OF:" at 11194.33,2295 h60
  text "X" at 10831.84,2166.37 h60
  text "ANSI IPC-A-600F CLASS ->" at 10959.84,2166.37 h60
  text "X" at 12607.84,2166.37 h60
  text "2" at 12717.84,2166.37 h60
  text "1" at 12402.84,2164.88 h60
  text "3" at 13071.84,2164.88 h60
  text "X" at 11643.84,2018.69 h60
  text "RoHS" at 11771.84,2018.69 h60
  text "OTHER" at 12416.24,2018.69 h60
  text "PER ORDER" at 12813.3,2018.69 h60
  text "ALL BOARDS MUST MEET OR EXCEED UL94-V0 REQUIREMENTS." at 10496.88,1864.86 h60
  text "PCB MUST BEAR THE UL94V-0 UL REGISTERED MATERIAL ID NUMBER" at 10496.88,1748.8 h55
  text "ADDITIONAL REQUIREMENTS:" at 10469.33,1579.37 h60
  text "MICROSECTION:" at 10544.1,1472.25 h60
  text "YES" at 11449.84,1472.25 h60
  text "REQUIRED" at 12311.33,1327.92 h60
  text "BARE BOARD ELEC. TEST:" at 10544.1,1325.06 h60
  text "NONE" at 11849.84,1325.06 h60
  text "X" at 12193.34,1325.06 h60
  text "PER ORDER" at 12903.33,1325.06 h60
  text "XX MIL VIAS REQUIRE NON-CONDUCTIVE FILL AND PLANARIZE" at 10712.25,1120.11 h59
  text "XX MIL VIAS REQUIRE CONDUCTIVE FILL AND PLANARIZE" at 10720.25,1016.14 h60
  text "OUTER XX MIL TRACES REQUIRE 50 OHM SINGLE-ENDED IMPEDANCE" at 10719.27,852.75 h55
  text "LAYER 2 & 3 (INNER LAYERS) XX MIL WIDE, XX MIL SPACE / TRACES REQUIRE 100 OHM DIFFERENTIAL IMPEDANCE" at 10711.27,617.04 h60
  text ".Layer_Name" at -287.12,-1133.2 h60
M11 Gerber Information:
  circle w10: c4300.74,4402.75 r100
  circle w10: c4300.74,4402.75 r50
  circle w10: c4302.1,-252.68 r50
  circle w10: c4302.1,-252.68 r100
  circle w10: c-1.04,4397.03 r50
  circle w10: c-1.04,4397.03 r100
  lines w10: -1156.12,-1204.87 5443.88,-1204.87 ; -1156.12,-1001.54 5445.88,-1001.54 ; -1156.12,-798.21 -1156.12,-1408.21 2848.88,-1408.21 5445.88,-1408.21 5445.88,-798.21 -1155.62,-798.21 -1155.62,-1408.21 419.88,-1408.21 ; -151.04,4397.03 148.96,4397.03 ; -1.04,4247.03 -1.04,4547.03 ; 908.61,-1002.14 908.61,-798.81 ; 1229.22,-1204.87 1229.22,-1001.54 ; 1352.67,-1408.21 1352.67,-1204.87 ; 2575.88,-1001.54 2575.88,-798.21 ; 3415.88,-1001.54 3415.88,-798.21 ; 4037.88,-1414.71 4037.88,-1211.87 ; 4150.74,4402.75 4450.74,4402.75 ; 4152.1,-252.68 4452.1,-252.68 ; 4300.74,4252.75 4300.74,4552.75 ; 4302.1,-402.68 4302.1,-102.68
  text "BOARD #:" at 971.71,-925.66 h60
  text "MD129_DRV81325" at 1517.21,-925.66 h60
  text "ALL ARTWORK VIEWED FROM TOP SIDE" at -1092.62,-930.37 h60
  text "REV:" at 2773.88,-930.37 h60
  text "E1" at 3065.38,-930.37 h60
  text "SVN REV:" at 3611.88,-930.37 h60
  text ".VersionControl_RevNumber" at 4117.88,-930.37 h60
  text "LAYER NAME =" at -1092.62,-1133.2 h60
  text "TID #:" at 1383.88,-1133.71 h60
  text ".TID" at 1929.38,-1133.71 h60
  text "PLOT NAME =" at -1092.62,-1339.04 h60
  text ".plot_File_Name" at -287.12,-1339.04 h35
  text "GENERATED    :" at 1385.88,-1339.04 h60
  text ".Print_Date" at 2255.38,-1339.04 h60
  text ".Print_Time" at 2984.38,-1339.04 h60
  text "TEXAS INSTRUMENTS" at 4248.88,-1339.04 h60
M12 Stackup:
  lines w10: 3240.49,5241.18 3435.49,5241.18 ; 3240.49,5487.33 3435.49,5487.33 ; 3240.49,5728.09 3435.49,5728.09 ; 3241.22,5969.7 3436.22,5969.7 ; 3390.49,5196.18 3435.49,5241.18 ; 3390.49,5442.33 3435.49,5487.33 ; 3390.49,5683.09 3435.49,5728.09 ; 3391.22,5924.7 3436.22,5969.7 ; 3392.08,5284.59 3435.49,5241.18 ; 3392.08,5530.74 3435.49,5487.33 ; 3392.08,5771.51 3435.49,5728.09 ; 3392.8,6013.12 3436.22,5969.7
  lines w15: -178.63,5071.88 231.29,5071.88 1161.03,5071.88 2020.8,5071.88 2670.63,5071.88 3240.49,5071.88 ; -178.63,5191.88 231.29,5191.88 1161.03,5191.88 2020.8,5191.88 2670.63,5191.88 3240.49,5191.88 ; -178.63,5311.88 231.29,5311.88 1161.03,5311.88 2020.8,5311.88 2670.63,5311.88 3240.49,5311.88 ; -178.63,5431.88 231.29,5431.88 1161.03,5431.88 2020.8,5431.88 2670.63,5431.88 3240.49,5431.88 ; -178.63,5551.88 231.29,5551.88 1161.03,5551.88 2020.8,5551.88 2670.63,5551.88 3240.49,5551.88 ; -178.63,5671.88 231.29,5671.88 1161.03,5671.88 2020.8,5671.88 2670.63,5671.88 3240.49,5671.88 ; -178.63,5791.88 231.29,5791.88 1161.03,5791.88 2020.8,5791.88 2670.63,5791.88 3240.49,5791.88 ; -178.63,5911.88 231.29,5911.88 1161.03,5911.88 2020.8,5911.88 2670.63,5911.88 3240.49,5911.88 ; -178.63,6031.88 231.29,6031.88 1161.03,6031.88 2020.8,6031.88 2670.63,6031.88 3240.49,6031.88 ; -178.63,6151.88 231.29,6151.88 1161.03,6151.88 2020.8,6151.88 2670.63,6151.88 3240.49,6151.88 ; -178.63,6271.88 3240.49,6271.88 ; 231.29,6391.88 231.29,4951.88 ; 1161.03,6391.88 1161.03,4951.88 ; 2020.8,6391.88 2020.8,4951.88 ; 2670.63,6391.88 2670.63,4951.88 ; 231.29,4951.88 -178.63,4951.88 -178.63,6391.88 3240.49,6391.88 3240.49,4951.88 2670.63,4951.88 ; 231.29,4951.88 1161.03,4951.88 ; 1161.03,4951.88 2020.8,4951.88 ; 2020.8,4951.88 2670.63,4951.88
  text "STACK UP:" at -163.59,6426.66 h120
  text "Layer" at -108.63,6301.88 h60
  text "Name" at 301.29,6301.88 h60
  text "Material" at 1231.03,6301.88 h60
  text "Thickness" at 2090.8,6301.88 h60
  text "Constant" at 2740.63,6301.88 h60
  text "Top Overlay" at 301.29,6181.88 h60
  text "Top Solder" at 301.29,6061.88 h60
  text "Solder Resist" at 1231.03,6061.88 h60
  text "0.40mil" at 2090.8,6061.88 h60
  text "3.5" at 2740.63,6061.88 h60
  text "1" at -108.63,5941.88 h60
  text "Top Layer" at 301.29,5941.88 h60
  text "Copper" at 1231.03,5941.88 h60
  text "2.76mil" at 2090.8,5941.88 h60
  text "2 0Z (Copper + Plating)" at 3501.38,5933.12 h60
  text "Dielectric1" at 301.29,5821.88 h60
  text "FR-4 High Tg" at 1231.03,5821.88 h60
  text "59.20mil" at 2090.8,5821.88 h60
  text "4.8" at 2740.63,5821.88 h60
  text "2" at -108.63,5701.88 h60
  text "GND" at 301.29,5701.88 h60
  text "Copper" at 1231.03,5701.88 h60
  text "1.38mil" at 2090.8,5701.88 h60
  text "1 0Z" at 3500.66,5691.51 h60
  text "Dielectric 2" at 301.29,5581.88 h60
  text "FR-4 High Tg" at 1231.03,5581.88 h60
  text "12.60mil" at 2090.8,5581.88 h60
  text "4.8" at 2740.63,5581.88 h60
  text "3" at -108.63,5461.88 h60
  text "PWR" at 301.29,5461.88 h60
  text "Copper" at 1231.03,5461.88 h60
  text "1.38mil" at 2090.8,5461.88 h60
  text "1 0Z" at 3500.66,5450.74 h60
  text "Dielectric 3" at 301.29,5341.88 h60
  text "FR-4 High Tg" at 1231.03,5341.88 h60
  text "12.60mil" at 2090.8,5341.88 h60
  text "4.8" at 2740.63,5341.88 h60
  text "4" at -108.63,5221.88 h60
  text "Bottom Layer" at 301.29,5221.88 h60
  text "Copper" at 1231.03,5221.88 h60
  text "2.76mil" at 2090.8,5221.88 h60
  text "2 0Z (Copper + Plating)" at 3500.66,5204.59 h60
  text "Bottom Solder" at 301.29,5101.88 h60
  text "Solder Resist" at 1231.03,5101.88 h60
  text "0.40mil" at 2090.8,5101.88 h60
  text "3.5" at 2740.63,5101.88 h60
  text "Bottom Overlay" at 301.29,4981.88 h60
  text "Total board thickness:" at -108.63,4861.88 h60
  text "93.47mil" at 2090.8,4861.88 h60
  text ".Layer_Name" at -287.12,-1133.2 h60
M13 Component Bodies Top:
  text ".Layer_Name" at -287.12,-1133.2 h60
M14 Component Bodies Bottom:
  text ".Layer_Name" at -287.12,-1133.2 h60
M15 Courtyards Top:
  text ".Layer_Name" at -287.12,-1133.2 h60
M16 Courtyards Bottom:
  text ".Layer_Name" at -287.12,-1133.2 h60
Drill Drawing:
  circle w10: c5232.3,6000.39 r26.49
  lines w10: 5205.8,4900.9 5232.3,4914.15 5258.79,4900.9 5245.55,4927.39 5258.79,4953.89 5232.3,4940.64 5205.8,4953.89 5219.05,4927.39 5205.8,4900.9 ; 5205.8,5033.37 5219.05,5033.37 5219.05,5020.12 5245.55,5020.12 5245.55,5033.37 5258.79,5033.37 5258.79,5059.86 5245.55,5059.86 5245.55,5073.11 5219.05,5073.11 5219.05,5059.86 5205.8,5059.86 5205.8,5033.37 ; 5205.8,5165.84 5232.3,5139.34 5258.79,5165.84 5232.3,5192.33 5205.8,5165.84 ; 5205.8,5258.56 5205.8,5271.81 5219.05,5285.06 5205.8,5298.31 5205.8,5311.55 5219.05,5311.55 5232.3,5298.31 5245.55,5311.55 5258.79,5311.55 5258.79,5298.31 5245.55,5285.06 5258.79,5271.81 5258.79,5258.56 5245.55,5258.56 5232.3,5271.81 5219.05,5258.56 5205.8,5258.56 ; 5205.8,5497.01 5258.79,5497.01 5258.79,5550 5205.8,5550 5205.8,5497.01 ; 5205.8,5669.22 5258.79,5669.22 5232.3,5616.23 5205.8,5669.22 ; 5205.8,5788.44 5258.79,5788.44 5232.3,5735.45 5205.8,5788.44 ; 5205.8,5854.68 5232.3,5867.92 5258.79,5854.68 5245.55,5881.17 5258.79,5907.66 5232.3,5894.42 5205.8,5907.66 5219.05,5881.17 5205.8,5854.68 ; 5205.8,6106.37 5219.05,6106.37 5219.05,6093.12 5245.55,6093.12 5245.55,6106.37 5258.79,6106.37 5258.79,6132.86 5245.55,6132.86 5245.55,6146.11 5219.05,6146.11 5219.05,6132.86 5205.8,6132.86 5205.8,6106.37 ; 5205.8,6225.59 5219.05,6225.59 5232.3,6212.34 5245.55,6225.59 5258.79,6225.59 5245.55,6238.84 5258.79,6252.08 5245.55,6252.08 5232.3,6265.33 5219.05,6252.08 5205.8,6252.08 5219.05,6238.84 5205.8,6225.59 ; 5216.4,4911.5 5232.3,4919.44 5248.19,4911.5 5240.25,4927.39 5248.19,4943.29 5232.3,4935.34 5216.4,4943.29 5224.35,4927.39 5216.4,4911.5 ; 5216.4,5038.67 5224.35,5038.67 5224.35,5030.72 5240.25,5030.72 5240.25,5038.67 5248.19,5038.67 5248.19,5054.56 5240.25,5054.56 5240.25,5062.51 5224.35,5062.51 5224.35,5054.56 5216.4,5054.56 5216.4,5038.67 ; 5216.4,5658.62 5248.19,5658.62 5232.3,5626.83 5216.4,5658.62
  lines w15: 5157.64,4865.13 10097.28,4865.13 ; 5157.64,6295.8 10097.28,6295.8 ; 5602.05,4745.91 5602.05,6415.02 ; 6122.64,4745.91 6122.64,6415.02 ; 7000.79,4745.91 7000.79,6415.02 ; 7409.43,4745.91 7409.43,6415.02 ; 7999.24,4745.91 7999.24,6415.02 ; 9195.2,4745.91 9195.2,6415.02 ; 5157.64,4745.91 10097.28,4745.91 10097.28,6415.02 5157.64,6415.02 5157.64,4745.91
  text "DRILL TABLE:" at 5159.42,6493.62 h120
  text "Symbol" at 5229.17,6331.56 h57.23
  text "Count" at 5637.82,6331.56 h57.23
  text "Hole Size" at 6158.41,6331.56 h57.23
  text "Plated" at 7036.56,6331.56 h57.23
  text "Hole Type" at 7445.2,6331.56 h57.23
  text "Drill Layer Pair" at 8035,6331.56 h57.23
  text "Hole Tolerance" at 9230.97,6331.56 h57.23
  text "21" at 5637.82,6212.34 h47.69
  text "7.87mil (0.200mm)" at 6158.41,6212.34 h47.69
  text "PTH" at 7036.56,6212.34 h47.69
  text "Round" at 7445.2,6212.34 h47.69
  text "Top Layer - Bottom Layer" at 8035,6212.34 h47.69
  text "-3mil / +3mil" at 9230.97,6212.34 h47.69
  text "4" at 5637.82,6093.12 h47.69
  text "8.00mil (0.203mm)" at 6158.41,6093.12 h47.69
  text "PTH" at 7036.56,6093.12 h47.69
  text "Round" at 7445.2,6093.12 h47.69
  text "Top Layer - Bottom Layer" at 8035,6093.12 h47.69
  text "-3mil / +3mil" at 9230.97,6093.12 h47.69
  text "955" at 5637.82,5973.9 h47.69
  text "10.00mil (0.254mm)" at 6158.41,5973.9 h47.69
  text "PTH" at 7036.56,5973.9 h47.69
  text "Round" at 7445.2,5973.9 h47.69
  text "Top Layer - Bottom Layer" at 8035,5973.9 h47.69
  text "-3mil / +3mil" at 9230.97,5973.9 h47.69
  text "6" at 5637.82,5854.68 h47.69
  text "27.56mil (0.700mm)" at 6158.41,5854.68 h47.69
  text "PTH" at 7036.56,5854.68 h47.69
  text "Round" at 7445.2,5854.68 h47.69
  text "Top Layer - Bottom Layer" at 8035,5854.68 h47.69
  text "-3mil / +3mil" at 9230.97,5854.68 h47.69
  text "6" at 5637.82,5735.45 h47.69
  text "33.47mil (0.850mm)" at 6158.41,5735.45 h47.69
  text "PTH" at 7036.56,5735.45 h47.69
  text "Round" at 7445.2,5735.45 h47.69
  text "Top Layer - Bottom Layer" at 8035,5735.45 h47.69
  text "-3mil / +3mil" at 9230.97,5735.45 h47.69
  text "2" at 5637.82,5616.23 h47.69
  text "35.43mil (0.900mm)" at 6158.41,5616.23 h47.69
  text "PTH" at 7036.56,5616.23 h47.69
  text "Round" at 7445.2,5616.23 h47.69
  text "Top Layer - Bottom Layer" at 8035,5616.23 h47.69
  text "-3mil / +3mil" at 9230.97,5616.23 h47.69
  text "7" at 5637.82,5497.01 h47.69
  text "40.00mil (1.016mm)" at 6158.41,5497.01 h47.69
  text "PTH" at 7036.56,5497.01 h47.69
  text "Round" at 7445.2,5497.01 h47.69
  text "Top Layer - Bottom Layer" at 8035,5497.01 h47.69
  text "-3mil / +3mil" at 9230.97,5497.01 h47.69
  text "16" at 5637.82,5377.79 h47.69
  text "43.31mil (1.100mm)" at 6158.41,5377.79 h47.69
  text "PTH" at 7036.56,5377.79 h47.69
  text "Round" at 7445.2,5377.79 h47.69
  text "Top Layer - Bottom Layer" at 8035,5377.79 h47.69
  text "-3mil / +3mil" at 9230.97,5377.79 h47.69
  text "F" at 5204.64,5367.8 h52.99
  text "16" at 5637.82,5258.56 h47.69
  text "45.28mil (1.150mm)" at 6158.41,5258.56 h47.69
  text "PTH" at 7036.56,5258.56 h47.69
  text "Round" at 7445.2,5258.56 h47.69
  text "Top Layer - Bottom Layer" at 8035,5258.56 h47.69
  text "-3mil / +3mil" at 9230.97,5258.56 h47.69
  text "4" at 5637.82,5139.34 h47.69
  text "51.18mil (1.300mm)" at 6158.41,5139.34 h47.69
  text "PTH" at 7036.56,5139.34 h47.69
  text "Round" at 7445.2,5139.34 h47.69
  text "Top Layer - Bottom Layer" at 8035,5139.34 h47.69
  text "-3mil / +3mil" at 9230.97,5139.34 h47.69
  text "14" at 5637.82,5020.12 h47.69
  text "59.06mil (1.500mm)" at 6158.41,5020.12 h47.69
  text "PTH" at 7036.56,5020.12 h47.69
  text "Round" at 7445.2,5020.12 h47.69
  text "Top Layer - Bottom Layer" at 8035,5020.12 h47.69
  text "-3mil / +3mil" at 9230.97,5020.12 h47.69
  text "23" at 5637.82,4900.9 h47.69
  text "63.00mil (1.600mm)" at 6158.41,4900.9 h47.69
  text "PTH" at 7036.56,4900.9 h47.69
  text "Round" at 7445.2,4900.9 h47.69
  text "Top Layer - Bottom Layer" at 8035,4900.9 h47.69
  text "-3mil / +3mil" at 9230.97,4900.9 h47.69
  text "1074 Total" at 5637.82,4781.68 h47.69
  text ".Layer_Name" at -287.12,-1133.2 h60
M17 Embedded Cavity:
  text ".Layer_Name" at -287.12,-1133.2 h60
M18 Embedded Assembly:
  text ".Layer_Name" at -287.12,-1133.2 h60
M19 Embedded Keepout:
  text ".Layer_Name" at -287.12,-1133.2 h60

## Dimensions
4144.01,3842.18 to 4519.52,4215.59 on M2 Board Dimensions
171.55,3999.96 to 169.89,-0.04 on M2 Board Dimensions
0.82,3856.95 to 4300.82,3856.71 on M2 Board Dimensions
-864.12,-674.71 to 135.88,-674.71 on M2 Board Dimensions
